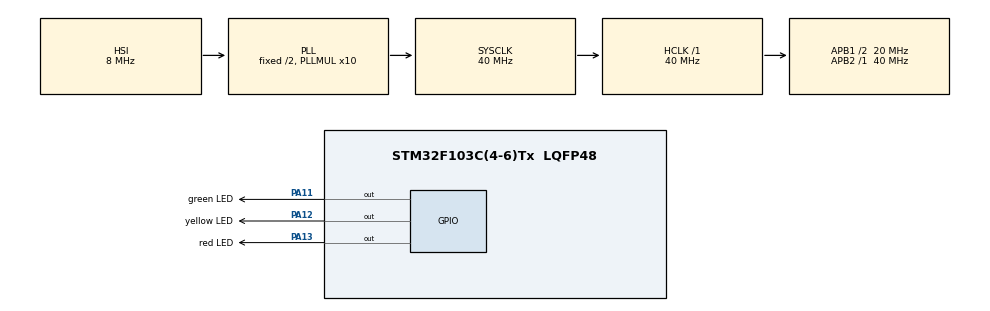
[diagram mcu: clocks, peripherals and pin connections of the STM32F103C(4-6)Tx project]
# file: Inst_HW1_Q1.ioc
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Mcu.Family=STM32F1
Mcu.Name=STM32F103C(4-6)Tx
Mcu.Package=LQFP48
NVIC.PriorityGroup=NVIC_PRIORITYGROUP_4
PA11.GPIO_Label=green LED
PA11.Signal=GPIO_Output
PA12.GPIO_Label=yellow LED
PA12.Signal=GPIO_Output
PA13.GPIO_Label=red LED
PA13.Signal=GPIO_Output
ProjectManager.HeapSize=0x200
ProjectManager.StackSize=0x400
ProjectManager.TargetToolchain=STM32CubeIDE
RCC.AHBFreq_Value=40000000
RCC.APB1CLKDivider=RCC_HCLK_DIV2
RCC.APB1Freq_Value=20000000
RCC.APB1TimFreq_Value=40000000
RCC.APB2Freq_Value=40000000
RCC.APB2TimFreq_Value=40000000
RCC.HCLKFreq_Value=40000000
RCC.PLLMUL=RCC_PLL_MUL10
RCC.SYSCLKFreq_VALUE=40000000
RCC.SYSCLKSource=RCC_SYSCLKSOURCE_PLLCLK
RCC.USBFreq_Value=40000000
board=custom

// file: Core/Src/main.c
/* USER CODE BEGIN Header */
/**
  ******************************************************************************
  * @file           : main.c
  * @brief          : Main program body
  ******************************************************************************
  * @attention
  *
  * Copyright (c) 2025 STMicroelectronics.
  * All rights reserved.
  *
  * This software is licensed under terms that can be found in the LICENSE file
  * in the root directory of this software component.
  * If no LICENSE file comes with this software, it is provided AS-IS.
  *
  ******************************************************************************
  */
/* USER CODE END Header */
#include "main.h"

void SystemClock_Config(void);
static void MX_GPIO_Init(void);

int main(void)
{

  /* MCU Configuration--------------------------------------------------------*/

  /* Reset of all peripherals, Initializes the Flash interface and the Systick. */
  HAL_Init();

  /* Configure the system clock */
  SystemClock_Config();

  /* Initialize all configured peripherals */
  MX_GPIO_Init();
  /* USER CODE BEGIN 2 */
  int press_number=0;
  int state=0;
  /* USER CODE END 2 */

  /* Infinite loop */
  /* USER CODE BEGIN WHILE */
  while (1)
  {
	  if (HAL_GPIO_ReadPin(BUTTON_GPIO_Port, BUTTON_Pin) == GPIO_PIN_RESET)
	  {
	      HAL_Delay(50);
	      while (HAL_GPIO_ReadPin(BUTTON_GPIO_Port, BUTTON_Pin) == GPIO_PIN_RESET);
	      HAL_Delay(50);
	      press_number++;
	      state = press_number % 3;

	  }
	  switch (state)
	  {
		  case 0:
			  HAL_GPIO_WritePin(green_LED_GPIO_Port,green_LED_Pin,GPIO_PIN_SET);
			  HAL_GPIO_WritePin(yellow_LED_GPIO_Port, yellow_LED_Pin,GPIO_PIN_RESET);
			  HAL_GPIO_WritePin(red_LED_GPIO_Port,red_LED_Pin,GPIO_PIN_RESET);
			  break;
		  case 1:

			  HAL_GPIO_WritePin(green_LED_GPIO_Port,green_LED_Pin,GPIO_PIN_RESET);
			  HAL_GPIO_WritePin(yellow_LED_GPIO_Port, yellow_LED_Pin,GPIO_PIN_SET );
			  HAL_GPIO_WritePin(red_LED_GPIO_Port,red_LED_Pin,GPIO_PIN_RESET);
			  break;
		  case 2:

			  HAL_GPIO_WritePin(green_LED_GPIO_Port,green_LED_Pin,GPIO_PIN_RESET);
			  HAL_GPIO_WritePin(yellow_LED_GPIO_Port, yellow_LED_Pin, GPIO_PIN_RESET);
			  HAL_GPIO_WritePin(red_LED_GPIO_Port,red_LED_Pin,GPIO_PIN_SET);
			  break;
		  default:
			  HAL_GPIO_WritePin(green_LED_GPIO_Port,green_LED_Pin,GPIO_PIN_SET);
			  HAL_GPIO_WritePin(yellow_LED_GPIO_Port, yellow_LED_Pin, GPIO_PIN_SET);
			  HAL_GPIO_WritePin(red_LED_GPIO_Port,red_LED_Pin,GPIO_PIN_SET);
	  }
    /* USER CODE END WHILE */

  }
}

void SystemClock_Config(void)
{
  RCC_OscInitTypeDef RCC_OscInitStruct = {0};
  RCC_ClkInitTypeDef RCC_ClkInitStruct = {0};

  /** Initializes the RCC Oscillators according to the specified parameters
  * in the RCC_OscInitTypeDef structure.
  */
  RCC_OscInitStruct.OscillatorType = RCC_OSCILLATORTYPE_HSI;
  RCC_OscInitStruct.HSIState = RCC_HSI_ON;
  RCC_OscInitStruct.HSICalibrationValue = RCC_HSICALIBRATION_DEFAULT;
  RCC_OscInitStruct.PLL.PLLState = RCC_PLL_ON;
  RCC_OscInitStruct.PLL.PLLSource = RCC_PLLSOURCE_HSI_DIV2;
  RCC_OscInitStruct.PLL.PLLMUL = RCC_PLL_MUL10;
  if (HAL_RCC_OscConfig(&RCC_OscInitStruct) != HAL_OK)
  {
    Error_Handler();
  }

  /** Initializes the CPU, AHB and APB buses clocks
  */
  RCC_ClkInitStruct.ClockType = RCC_CLOCKTYPE_HCLK|RCC_CLOCKTYPE_SYSCLK
                              |RCC_CLOCKTYPE_PCLK1|RCC_CLOCKTYPE_PCLK2;
  RCC_ClkInitStruct.SYSCLKSource = RCC_SYSCLKSOURCE_PLLCLK;
  RCC_ClkInitStruct.AHBCLKDivider = RCC_SYSCLK_DIV1;
  RCC_ClkInitStruct.APB1CLKDivider = RCC_HCLK_DIV2;
  RCC_ClkInitStruct.APB2CLKDivider = RCC_HCLK_DIV1;

  if (HAL_RCC_ClockConfig(&RCC_ClkInitStruct, FLASH_LATENCY_1) != HAL_OK)
  {
    Error_Handler();
  }
}

static void MX_GPIO_Init(void)
{
  GPIO_InitTypeDef GPIO_InitStruct = {0};

  /* GPIO Ports Clock Enable */
  __HAL_RCC_GPIOB_CLK_ENABLE();
  __HAL_RCC_GPIOA_CLK_ENABLE();

  /*Configure GPIO pin Output Level */
  HAL_GPIO_WritePin(GPIOA, detected_pb_Pin|green_LED_Pin|yellow_LED_Pin|red_LED_Pin, GPIO_PIN_RESET);

  /*Configure GPIO pin : BUTTON_Pin */
  GPIO_InitStruct.Pin = BUTTON_Pin;
  GPIO_InitStruct.Mode = GPIO_MODE_INPUT;
  GPIO_InitStruct.Pull = GPIO_PULLUP;
  HAL_GPIO_Init(BUTTON_GPIO_Port, &GPIO_InitStruct);

  /*Configure GPIO pins : detected_pb_Pin green_LED_Pin yellow_LED_Pin red_LED_Pin */
  GPIO_InitStruct.Pin = detected_pb_Pin|green_LED_Pin|yellow_LED_Pin|red_LED_Pin;
  GPIO_InitStruct.Mode = GPIO_MODE_OUTPUT_PP;
  GPIO_InitStruct.Pull = GPIO_NOPULL;
  GPIO_InitStruct.Speed = GPIO_SPEED_FREQ_LOW;
  HAL_GPIO_Init(GPIOA, &GPIO_InitStruct);

}

void Error_Handler(void)
{
  __disable_irq();
  while (1)
  {
  }
}
